VERSION 5.8 ;
BUSBITCHARS "[]" ;
DIVIDERCHAR "/" ;
UNITS
  DATABASE MICRONS 1000 ;
END UNITS
MANUFACTURINGGRID 0.005 ;

# Synthetic two-layer stack for the SAMEMASK end-of-line spacing correlation (every value
# invented). M2 is double-patterned and carries the rule; the reference checks it mask-blind.

PROPERTYDEFINITIONS
  LAYER LEF58_SPACING STRING ;
END PROPERTYDEFINITIONS

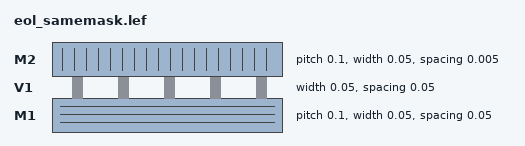
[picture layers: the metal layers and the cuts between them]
LAYER M1
  TYPE ROUTING ;
  DIRECTION HORIZONTAL ;
  PITCH 0.1 ;
  OFFSET 0.05 ;
  WIDTH 0.05 ;
  SPACING 0.05 ;
END M1
LAYER V1
  TYPE CUT ;
  SPACING 0.05 ;
  WIDTH 0.05 ;
END V1
LAYER M2
  TYPE ROUTING ;
  DIRECTION VERTICAL ;
  PITCH 0.1 ;
  OFFSET 0.05 ;
  WIDTH 0.05 ;
  SPACING 0.005 ;
  MASK 2 ;
  PROPERTY LEF58_SPACING "SPACING 0.07 ENDOFLINE 0.06 WITHIN 0.02 SAMEMASK ENDTOEND 0.08 EXTENSION 0.01 MINLENGTH 0.02 TWOSIDES ;" ;
END M2
END LIBRARY
